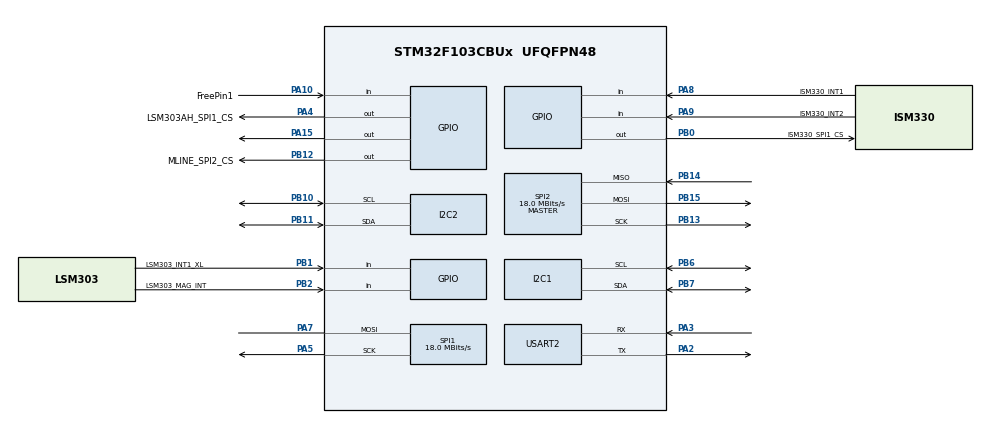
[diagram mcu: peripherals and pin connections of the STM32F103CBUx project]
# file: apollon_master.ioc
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Mcu.Family=STM32F1
NVIC.DMA1_Channel5_IRQn=true\:0\:0\:false\:false\:true\:true\:false\:true
SPI1.VirtualType=VM_MASTER
SPI2.VirtualType=VM_MASTER
PB10.Mode=I2C
Dma.USART2_TX.1.MemInc=DMA_MINC_ENABLE
PB0.GPIO_Label=ISM330_SPI1_CS
NVIC.TIM1_UP_IRQn=true\:0\:0\:false\:false\:true\:false\:true\:true
PB11.Signal=I2C2_SDA
PB13.Signal=SPI2_SCK
PB15.Signal=SPI2_MOSI
RCC.SYSCLKSource=RCC_SYSCLKSOURCE_PLLCLK
ProjectManager.StackSize=0x400
VP_FREERTOS_VS_CMSIS_V2.Mode=CMSIS_V2
PD1-OSC_OUT.Signal=RCC_OSC_OUT
FREERTOS.INCLUDE_pcTaskGetTaskName=1
TIM1.Prescaler=719
SPI1.CLKPolarity=SPI_POLARITY_HIGH
Mcu.UserConstants=sensor_LSM303AH_SPI1,1;sensor_ISM330_SPI1,1;sensor_BMP280_I2C2,1
Dma.USART2_RX.0.Priority=DMA_PRIORITY_LOW
Dma.SPI2_RX.2.Direction=DMA_PERIPH_TO_MEMORY
FREERTOS.configUSE_STATS_FORMATTING_FUNCTIONS=1
SPI1.Direction=SPI_DIRECTION_1LINE
Dma.USART2_RX.0.PeriphDataAlignment=DMA_PDATAALIGN_BYTE
RCC.HCLKFreq_Value=72000000
RCC.APB2TimFreq_Value=72000000
PB6.Signal=I2C1_SCL
Dma.USART2_TX.1.Mode=DMA_NORMAL
PB6.Mode=I2C
SPI1.CalculateBaudRate=18.0 MBits/s
Dma.SPI2_TX.3.Priority=DMA_PRIORITY_LOW
RCC.AHBFreq_Value=72000000
SPI2.BaudRatePrescaler=SPI_BAUDRATEPRESCALER_2
Dma.SPI2_RX.2.Instance=DMA1_Channel4
Dma.SPI2_RX.2.MemDataAlignment=DMA_MDATAALIGN_BYTE
PB2.Signal=GPIO_Input
Dma.SPI2_RX.2.PeriphInc=DMA_PINC_DISABLE
RCC.PLLMUL=RCC_PLL_MUL9
PB12.GPIO_Label=MLINE_SPI2_CS
Dma.USART2_RX.0.MemDataAlignment=DMA_MDATAALIGN_BYTE
PC14-OSC32_IN.Mode=LSE-External-Oscillator
PA14.Mode=Serial_Wire
Dma.USART2_TX.1.Instance=DMA1_Channel7
PB14.Mode=Full_Duplex_Master
FREERTOS.HEAP_NUMBER=1
PB1.GPIO_Label=LSM303_INT1_XL
NVIC.TIM2_IRQn=true\:0\:0\:false\:false\:true\:false\:false\:true
PA10.GPIO_Label=FreePin1
Dma.USART2_RX.0.Instance=DMA1_Channel6
SPI2.CalculateBaudRate=18.0 MBits/s
PB7.Signal=I2C1_SDA
Dma.SPI2_RX.2.PeriphDataAlignment=DMA_PDATAALIGN_BYTE
PA8.Signal=GPIO_Input
FREERTOS.INCLUDE_vTaskCleanUpResources=1
VP_TIM1_VS_ClockSourceINT.Mode=Internal
Mcu.Package=UFQFPN48
VP_SYS_VS_tim2.Mode=TIM2
PB1.Signal=GPIO_Input
FREERTOS.INCLUDE_xTaskAbortDelay=1
NVIC.TimeBase=TIM2_IRQn
SPI2.Mode=SPI_MODE_MASTER
Dma.USART2_RX.0.PeriphInc=DMA_PINC_DISABLE
Dma.SPI2_RX.2.Priority=DMA_PRIORITY_LOW
USART2.VirtualMode=VM_ASYNC
Dma.SPI2_RX.2.MemInc=DMA_MINC_ENABLE
NVIC.TimeBaseIP=TIM2
PA10.Signal=GPIO_Input
PA15.Signal=GPIO_Output
Dma.Request2=SPI2_RX
Dma.Request1=USART2_TX
RCC.APB1TimFreq_Value=72000000
FREERTOS.configGENERATE_RUN_TIME_STATS=1
Dma.Request3=SPI2_TX
SPI2.Direction=SPI_DIRECTION_2LINES
TIM1.Period=10
PB13.Mode=Full_Duplex_Master
NVIC.DMA1_Channel4_IRQn=true\:0\:0\:false\:false\:true\:true\:false\:true
Dma.Request0=USART2_RX
SPI1.BaudRatePrescaler=SPI_BAUDRATEPRESCALER_4
PA4.GPIO_Label=LSM303AH_SPI1_CS
VP_TIM3_VS_ClockSourceINT.Mode=Internal
Dma.SPI2_TX.3.Direction=DMA_MEMORY_TO_PERIPH
PA3.Signal=USART2_RX
PA5.Mode=Simplex_Bidirectional_Master
Dma.SPI2_TX.3.MemInc=DMA_MINC_ENABLE
RCC.PLLSourceVirtual=RCC_PLLSOURCE_HSE
PC15-OSC32_OUT.Mode=LSE-External-Oscillator
NVIC.DMA1_Channel6_IRQn=true\:5\:0\:true\:false\:true\:true\:false\:true
Dma.USART2_TX.1.Priority=DMA_PRIORITY_LOW
FREERTOS.Tasks01=dataCollectTask,16,128,startDataCollectTask,Default,NULL,Dynamic,NULL,NULL;sensorTask,8,128,startSensorTask,Default,NULL,Dynamic,NULL,NULL;spiTxMlineTask,24,128,startSpiTxMlineTask,Default,NULL,Static,spiTxMlineTaskBuffer,spiTxMlineTaskControlBlock;spiRxMlineTask,24,128,startSpiRxMlineTask,Default,NULL,Static,spiRxMlineTaskBuffer,spiRxMlineTaskControlBlock;uartTxTask,32,128,startUartTxTask,Default,NULL,Static,UartTxTaskBuffer,UartTxTaskControlBlock;uartRxTask,8,128,startUartRxTask,Default,NULL,Static,UartRxTaskBuffer,UartRxTaskControlBlock;superVisorTask,8,128,startSuperVisorTask,Default,NULL,Static,superVisorTaskBuffer,superVisorTaskControlBlock
PA7.Mode=Simplex_Bidirectional_Master
PD1-OSC_OUT.Mode=HSE-External-Oscillator
TIM3.AutoReloadPreload=TIM_AUTORELOAD_PRELOAD_ENABLE
Dma.SPI2_TX.3.MemDataAlignment=DMA_MDATAALIGN_BYTE
FREERTOS.INCLUDE_xTaskGetCurrentTaskHandle=1
PA9.GPIO_Label=ISM330_INT2
Dma.USART2_RX.0.Direction=DMA_PERIPH_TO_MEMORY
SPI1.CLKPhase=SPI_PHASE_2EDGE
PD0-OSC_IN.Signal=RCC_OSC_IN
RCC.APB1CLKDivider=RCC_HCLK_DIV2
PC14-OSC32_IN.Signal=RCC_OSC32_IN
Dma.USART2_TX.1.PeriphDataAlignment=DMA_PDATAALIGN_BYTE
Dma.USART2_RX.0.Mode=DMA_NORMAL
Dma.SPI2_RX.2.Mode=DMA_NORMAL
Dma.SPI2_TX.3.PeriphDataAlignment=DMA_PDATAALIGN_BYTE
PA13.Signal=SYS_JTMS-SWDIO
PA3.Mode=Asynchronous
TIM1.AutoReloadPreload=TIM_AUTORELOAD_PRELOAD_ENABLE
PA8.GPIO_Label=ISM330_INT1
PB11.Mode=I2C
ProjectManager.TargetToolchain=Makefile
PA9.Signal=GPIO_Input
Dma.SPI2_TX.3.Mode=DMA_NORMAL
RCC.USBFreq_Value=72000000
PC15-OSC32_OUT.Signal=RCC_OSC32_OUT
PD0-OSC_IN.Mode=HSE-External-Oscillator
PB10.Signal=I2C2_SCL
PB14.Signal=SPI2_MISO
PA5.Signal=SPI1_SCK
Dma.USART2_TX.1.PeriphInc=DMA_PINC_DISABLE
board=custom
PB15.Mode=Full_Duplex_Master
NVIC.TIM3_IRQn=true\:0\:0\:false\:false\:true\:true\:true\:true
Dma.USART2_TX.1.Direction=DMA_MEMORY_TO_PERIPH
TIM1.TIM_MasterOutputTrigger=TIM_TRGO_UPDATE
Dma.SPI2_TX.3.Instance=DMA1_Channel5
RCC.APB2Freq_Value=72000000
SPI1.Mode=SPI_MODE_MASTER
FREERTOS.INCLUDE_xEventGroupSetBitFromISR=1
PA13.Mode=Serial_Wire
Mcu.Name=STM32F103CBUx
Dma.USART2_RX.0.MemInc=DMA_MINC_ENABLE
FREERTOS.INCLUDE_xSemaphoreGetMutexHolder=1
PA2.Signal=USART2_TX
PA4.Signal=GPIO_Output
RCC.SYSCLKFreq_VALUE=72000000
PB7.Mode=I2C
PA14.Signal=SYS_JTCK-SWCLK
PB2.GPIO_Label=LSM303_MAG_INT
ProjectManager.HeapSize=0x200
FREERTOS.INCLUDE_xTaskGetHandle=1
NVIC.PriorityGroup=NVIC_PRIORITYGROUP_4
Dma.SPI2_TX.3.PeriphInc=DMA_PINC_DISABLE
PA2.Mode=Asynchronous
NVIC.DMA1_Channel7_IRQn=true\:5\:0\:true\:false\:true\:true\:false\:true
Dma.USART2_TX.1.MemDataAlignment=DMA_MDATAALIGN_BYTE
TIM3.TIM_MasterOutputTrigger=TIM_TRGO_UPDATE
RCC.APB1Freq_Value=36000000
PB0.Signal=GPIO_Output
PB12.Signal=GPIO_Output
PA7.Signal=SPI1_MOSI

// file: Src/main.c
/* USER CODE BEGIN Header */
/**
  ******************************************************************************
  * @file           : main.c
  * @brief          : Main program body
  ******************************************************************************
  * @attention
  *
  * <h2><center>&copy; Copyright (c) 2020 STMicroelectronics.
  * All rights reserved.</center></h2>
  *
  * This software component is licensed by ST under Ultimate Liberty license
  * SLA0044, the "License"; You may not use this file except in compliance with
  * the License. You may obtain a copy of the License at:
  *                             www.st.com/SLA0044
  *
  ******************************************************************************
  */
/* USER CODE END Header */
#include "main.h"
#include "cmsis_os.h"
#include "dma.h"
#include "i2c.h"
#include "spi.h"
#include "tim.h"
#include "usart.h"
#include "gpio.h"

void SystemClock_Config(void);
void MX_FREERTOS_Init(void);

int main(void)
{

  /* MCU Configuration--------------------------------------------------------*/

  /* Reset of all peripherals, Initializes the Flash interface and the Systick. */
  HAL_Init();

  /* Configure the system clock */
  SystemClock_Config();

  /* Initialize all configured peripherals */
  MX_GPIO_Init();
  MX_DMA_Init();
  MX_I2C1_Init();
  MX_SPI1_Init();
  MX_I2C2_Init();
  MX_SPI2_Init();
  MX_USART2_UART_Init();
  MX_TIM1_Init();
  MX_TIM3_Init();

  /* Init scheduler */
  osKernelInitialize();  /* Call init function for freertos objects (in freertos.c) */
  MX_FREERTOS_Init();
  /* Start scheduler */
  osKernelStart();

  /* We should never get here as control is now taken by the scheduler */
  /* Infinite loop */
  while (1)
  {

  }
}

void SystemClock_Config(void)
{
  RCC_OscInitTypeDef RCC_OscInitStruct = {0};
  RCC_ClkInitTypeDef RCC_ClkInitStruct = {0};

  /** Initializes the RCC Oscillators according to the specified parameters
  * in the RCC_OscInitTypeDef structure.
  */
  RCC_OscInitStruct.OscillatorType = RCC_OSCILLATORTYPE_HSE;
  RCC_OscInitStruct.HSEState = RCC_HSE_ON;
  RCC_OscInitStruct.PLL.PLLState = RCC_PLL_NONE;
  if (HAL_RCC_OscConfig(&RCC_OscInitStruct) != HAL_OK)
  {
    Error_Handler();
  }
  /** Initializes the CPU, AHB and APB buses clocks
  */
  RCC_ClkInitStruct.ClockType = RCC_CLOCKTYPE_HCLK|RCC_CLOCKTYPE_SYSCLK
                              |RCC_CLOCKTYPE_PCLK1|RCC_CLOCKTYPE_PCLK2;
  RCC_ClkInitStruct.SYSCLKSource = RCC_SYSCLKSOURCE_HSE;
  RCC_ClkInitStruct.AHBCLKDivider = RCC_SYSCLK_DIV1;
  RCC_ClkInitStruct.APB1CLKDivider = RCC_HCLK_DIV2;
  RCC_ClkInitStruct.APB2CLKDivider = RCC_HCLK_DIV1;

  if (HAL_RCC_ClockConfig(&RCC_ClkInitStruct, FLASH_LATENCY_0) != HAL_OK)
  {
    Error_Handler();
  }
}

void HAL_TIM_PeriodElapsedCallback(TIM_HandleTypeDef *htim)
{
  if (htim->Instance == TIM2) {
    HAL_IncTick();
  }
}

void Error_Handler(void)
{
}

/************************ (C) COPYRIGHT STMicroelectronics *****END OF FILE****/
